One B-rep face of a CAD part: STEP entity #65022.
In plain terms, the planar face has unit normal (0, 0, 1).
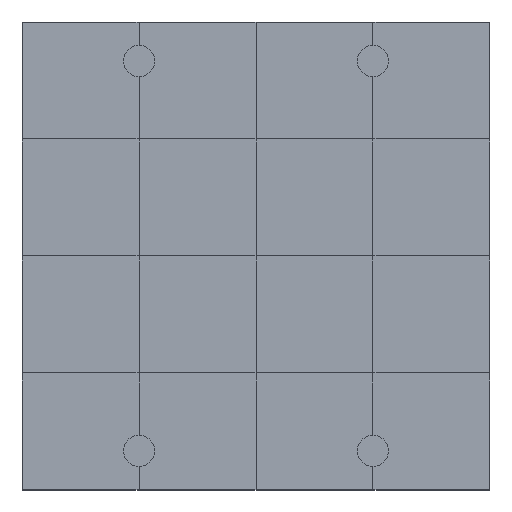
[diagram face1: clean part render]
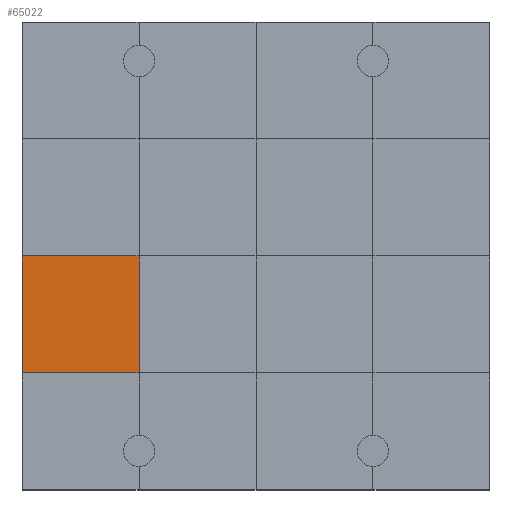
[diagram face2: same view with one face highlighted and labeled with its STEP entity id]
Its self-contained STEP definition (entity closure, numbers rounded to 3 decimals):
#64572 = VERTEX_POINT('',#64573);
#64573 = CARTESIAN_POINT('',(0.,3.,1.2));
#64587 = PLANE('',#64588);
#64588 = AXIS2_PLACEMENT_3D('',#64589,#64590,#64591);
#64589 = CARTESIAN_POINT('',(0.,3.,0.));
#64590 = DIRECTION('',(1.,0.,-0.));
#64591 = DIRECTION('',(0.,0.,1.));
#64613 = PLANE('',#64614);
#64614 = AXIS2_PLACEMENT_3D('',#64615,#64616,#64617);
#64615 = CARTESIAN_POINT('',(0.,0.,1.2));
#64616 = DIRECTION('',(0.,0.,1.));
#64617 = DIRECTION('',(1.,0.,-0.));
#64764 = VERTEX_POINT('',#64765);
#64765 = CARTESIAN_POINT('',(3.,3.,1.2));
#64786 = EDGE_CURVE('',#64572,#64764,#64787,.T.);
#64787 = SURFACE_CURVE('',#64788,(#64792,#64799),.PCURVE_S1.);
#64788 = LINE('',#64789,#64790);
#64789 = CARTESIAN_POINT('',(0.,3.,1.2));
#64790 = VECTOR('',#64791,1.);
#64791 = DIRECTION('',(1.,0.,-0.));
#64792 = PCURVE('',#64613,#64793);
#64793 = DEFINITIONAL_REPRESENTATION('',(#64794),#64798);
#64794 = LINE('',#64795,#64796);
#64795 = CARTESIAN_POINT('',(0.,3.));
#64796 = VECTOR('',#64797,1.);
#64797 = DIRECTION('',(1.,0.));
#64798 = ( GEOMETRIC_REPRESENTATION_CONTEXT(2) 
PARAMETRIC_REPRESENTATION_CONTEXT() REPRESENTATION_CONTEXT('2D SPACE',''
  ) );
#64799 = PCURVE('',#64800,#64805);
#64800 = PLANE('',#64801);
#64801 = AXIS2_PLACEMENT_3D('',#64802,#64803,#64804);
#64802 = CARTESIAN_POINT('',(0.,3.,1.2));
#64803 = DIRECTION('',(0.,0.,1.));
#64804 = DIRECTION('',(1.,0.,-0.));
#64805 = DEFINITIONAL_REPRESENTATION('',(#64806),#64810);
#64806 = LINE('',#64807,#64808);
#64807 = CARTESIAN_POINT('',(0.,0.));
#64808 = VECTOR('',#64809,1.);
#64809 = DIRECTION('',(1.,0.));
#64810 = ( GEOMETRIC_REPRESENTATION_CONTEXT(2) 
PARAMETRIC_REPRESENTATION_CONTEXT() REPRESENTATION_CONTEXT('2D SPACE',''
  ) );
#64845 = VERTEX_POINT('',#64846);
#64846 = CARTESIAN_POINT('',(0.,6.,1.2));
#64872 = EDGE_CURVE('',#64572,#64845,#64873,.T.);
#64873 = SURFACE_CURVE('',#64874,(#64878,#64885),.PCURVE_S1.);
#64874 = LINE('',#64875,#64876);
#64875 = CARTESIAN_POINT('',(0.,3.,1.2));
#64876 = VECTOR('',#64877,1.);
#64877 = DIRECTION('',(-0.,1.,0.));
#64878 = PCURVE('',#64587,#64879);
#64879 = DEFINITIONAL_REPRESENTATION('',(#64880),#64884);
#64880 = LINE('',#64881,#64882);
#64881 = CARTESIAN_POINT('',(1.2,0.));
#64882 = VECTOR('',#64883,1.);
#64883 = DIRECTION('',(0.,-1.));
#64884 = ( GEOMETRIC_REPRESENTATION_CONTEXT(2) 
PARAMETRIC_REPRESENTATION_CONTEXT() REPRESENTATION_CONTEXT('2D SPACE',''
  ) );
#64885 = PCURVE('',#64800,#64886);
#64886 = DEFINITIONAL_REPRESENTATION('',(#64887),#64891);
#64887 = LINE('',#64888,#64889);
#64888 = CARTESIAN_POINT('',(0.,0.));
#64889 = VECTOR('',#64890,1.);
#64890 = DIRECTION('',(0.,1.));
#64891 = ( GEOMETRIC_REPRESENTATION_CONTEXT(2) 
PARAMETRIC_REPRESENTATION_CONTEXT() REPRESENTATION_CONTEXT('2D SPACE',''
  ) );
#65022 = ADVANCED_FACE('',(#65023),#64800,.T.);
#65023 = FACE_BOUND('',#65024,.T.);
#65024 = EDGE_LOOP('',(#65025,#65026,#65027,#65055));
#65025 = ORIENTED_EDGE('',*,*,#64872,.F.);
#65026 = ORIENTED_EDGE('',*,*,#64786,.T.);
#65027 = ORIENTED_EDGE('',*,*,#65028,.T.);
#65028 = EDGE_CURVE('',#64764,#65029,#65031,.T.);
#65029 = VERTEX_POINT('',#65030);
#65030 = CARTESIAN_POINT('',(3.,6.,1.2));
#65031 = SURFACE_CURVE('',#65032,(#65036,#65043),.PCURVE_S1.);
#65032 = LINE('',#65033,#65034);
#65033 = CARTESIAN_POINT('',(3.,3.,1.2));
#65034 = VECTOR('',#65035,1.);
#65035 = DIRECTION('',(-0.,1.,0.));
#65036 = PCURVE('',#64800,#65037);
#65037 = DEFINITIONAL_REPRESENTATION('',(#65038),#65042);
#65038 = LINE('',#65039,#65040);
#65039 = CARTESIAN_POINT('',(3.,0.));
#65040 = VECTOR('',#65041,1.);
#65041 = DIRECTION('',(0.,1.));
#65042 = ( GEOMETRIC_REPRESENTATION_CONTEXT(2) 
PARAMETRIC_REPRESENTATION_CONTEXT() REPRESENTATION_CONTEXT('2D SPACE',''
  ) );
#65043 = PCURVE('',#65044,#65049);
#65044 = PLANE('',#65045);
#65045 = AXIS2_PLACEMENT_3D('',#65046,#65047,#65048);
#65046 = CARTESIAN_POINT('',(3.,3.,1.2));
#65047 = DIRECTION('',(0.,0.,1.));
#65048 = DIRECTION('',(1.,0.,-0.));
#65049 = DEFINITIONAL_REPRESENTATION('',(#65050),#65054);
#65050 = LINE('',#65051,#65052);
#65051 = CARTESIAN_POINT('',(0.,0.));
#65052 = VECTOR('',#65053,1.);
#65053 = DIRECTION('',(0.,1.));
#65054 = ( GEOMETRIC_REPRESENTATION_CONTEXT(2) 
PARAMETRIC_REPRESENTATION_CONTEXT() REPRESENTATION_CONTEXT('2D SPACE',''
  ) );
#65055 = ORIENTED_EDGE('',*,*,#65056,.F.);
#65056 = EDGE_CURVE('',#64845,#65029,#65057,.T.);
#65057 = SURFACE_CURVE('',#65058,(#65062,#65069),.PCURVE_S1.);
#65058 = LINE('',#65059,#65060);
#65059 = CARTESIAN_POINT('',(0.,6.,1.2));
#65060 = VECTOR('',#65061,1.);
#65061 = DIRECTION('',(1.,0.,-0.));
#65062 = PCURVE('',#64800,#65063);
#65063 = DEFINITIONAL_REPRESENTATION('',(#65064),#65068);
#65064 = LINE('',#65065,#65066);
#65065 = CARTESIAN_POINT('',(0.,3.));
#65066 = VECTOR('',#65067,1.);
#65067 = DIRECTION('',(1.,0.));
#65068 = ( GEOMETRIC_REPRESENTATION_CONTEXT(2) 
PARAMETRIC_REPRESENTATION_CONTEXT() REPRESENTATION_CONTEXT('2D SPACE',''
  ) );
#65069 = PCURVE('',#65070,#65075);
#65070 = PLANE('',#65071);
#65071 = AXIS2_PLACEMENT_3D('',#65072,#65073,#65074);
#65072 = CARTESIAN_POINT('',(0.,6.,1.2));
#65073 = DIRECTION('',(0.,0.,1.));
#65074 = DIRECTION('',(1.,0.,-0.));
#65075 = DEFINITIONAL_REPRESENTATION('',(#65076),#65080);
#65076 = LINE('',#65077,#65078);
#65077 = CARTESIAN_POINT('',(0.,0.));
#65078 = VECTOR('',#65079,1.);
#65079 = DIRECTION('',(1.,0.));
#65080 = ( GEOMETRIC_REPRESENTATION_CONTEXT(2) 
PARAMETRIC_REPRESENTATION_CONTEXT() REPRESENTATION_CONTEXT('2D SPACE',''
  ) );
